# Generated deterministically by seda-macro-lef-normalizer-v1; recipe orfs-asap7-fakeram-m4-v1.
VERSION 5.8 ;
BUSBITCHARS "[]" ;
DIVIDERCHAR "/" ;

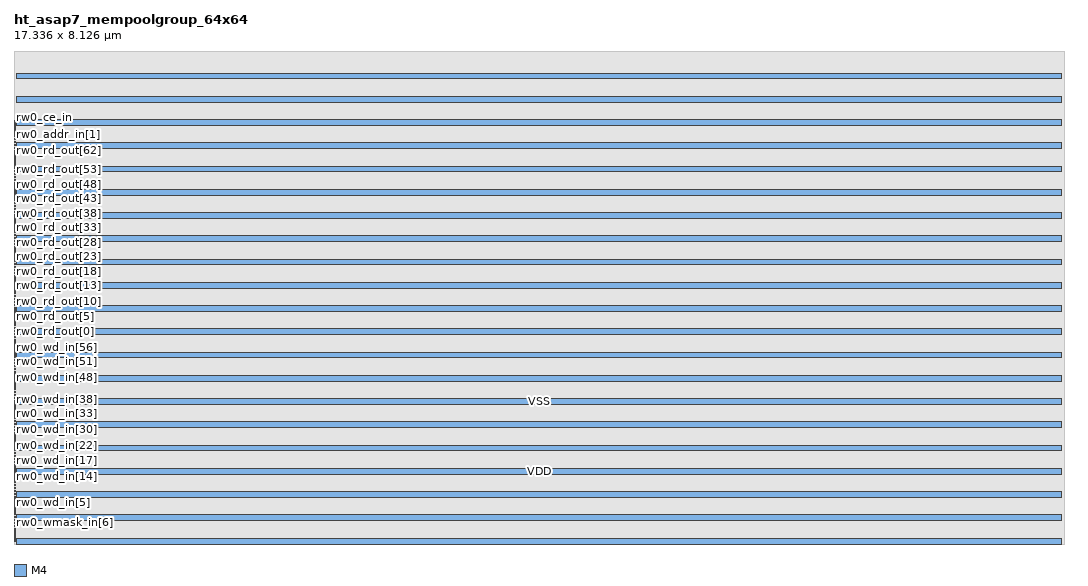
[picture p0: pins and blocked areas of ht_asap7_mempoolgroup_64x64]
MACRO ht_asap7_mempoolgroup_64x64
  FOREIGN ht_asap7_mempoolgroup_64x64 0 0 ;
  CLASS BLOCK ;
  ORIGIN 0 0 ;
  SIZE 17.336 BY 8.126 ;
  SYMMETRY X Y R90 ;
  PIN rw0_wmask_in[0]
    DIRECTION INPUT ;
    USE SIGNAL ;
    SHAPE ABUTMENT ;
    PORT
      LAYER M4 ;
      RECT 0 0.048 0.024 0.072 ;
    END
  END rw0_wmask_in[0]
  PIN rw0_wmask_in[1]
    DIRECTION INPUT ;
    USE SIGNAL ;
    SHAPE ABUTMENT ;
    PORT
      LAYER M4 ;
      RECT 0 0.096 0.024 0.12 ;
    END
  END rw0_wmask_in[1]
  PIN rw0_wmask_in[2]
    DIRECTION INPUT ;
    USE SIGNAL ;
    SHAPE ABUTMENT ;
    PORT
      LAYER M4 ;
      RECT 0 0.144 0.024 0.168 ;
    END
  END rw0_wmask_in[2]
  PIN rw0_wmask_in[3]
    DIRECTION INPUT ;
    USE SIGNAL ;
    SHAPE ABUTMENT ;
    PORT
      LAYER M4 ;
      RECT 0 0.192 0.024 0.216 ;
    END
  END rw0_wmask_in[3]
  PIN rw0_wmask_in[4]
    DIRECTION INPUT ;
    USE SIGNAL ;
    SHAPE ABUTMENT ;
    PORT
      LAYER M4 ;
      RECT 0 0.24 0.024 0.264 ;
    END
  END rw0_wmask_in[4]
  PIN rw0_wmask_in[5]
    DIRECTION INPUT ;
    USE SIGNAL ;
    SHAPE ABUTMENT ;
    PORT
      LAYER M4 ;
      RECT 0 0.288 0.024 0.312 ;
    END
  END rw0_wmask_in[5]
  PIN rw0_wmask_in[6]
    DIRECTION INPUT ;
    USE SIGNAL ;
    SHAPE ABUTMENT ;
    PORT
      LAYER M4 ;
      RECT 0 0.336 0.024 0.36 ;
    END
  END rw0_wmask_in[6]
  PIN rw0_wmask_in[7]
    DIRECTION INPUT ;
    USE SIGNAL ;
    SHAPE ABUTMENT ;
    PORT
      LAYER M4 ;
      RECT 0 0.384 0.024 0.408 ;
    END
  END rw0_wmask_in[7]
  PIN rw0_wd_in[0]
    DIRECTION INPUT ;
    USE SIGNAL ;
    SHAPE ABUTMENT ;
    PORT
      LAYER M4 ;
      RECT 0 0.432 0.024 0.456 ;
    END
  END rw0_wd_in[0]
  PIN rw0_wd_in[1]
    DIRECTION INPUT ;
    USE SIGNAL ;
    SHAPE ABUTMENT ;
    PORT
      LAYER M4 ;
      RECT 0 0.48 0.024 0.504 ;
    END
  END rw0_wd_in[1]
  PIN rw0_wd_in[2]
    DIRECTION INPUT ;
    USE SIGNAL ;
    SHAPE ABUTMENT ;
    PORT
      LAYER M4 ;
      RECT 0 0.528 0.024 0.552 ;
    END
  END rw0_wd_in[2]
  PIN rw0_wd_in[3]
    DIRECTION INPUT ;
    USE SIGNAL ;
    SHAPE ABUTMENT ;
    PORT
      LAYER M4 ;
      RECT 0 0.576 0.024 0.6 ;
    END
  END rw0_wd_in[3]
  PIN rw0_wd_in[4]
    DIRECTION INPUT ;
    USE SIGNAL ;
    SHAPE ABUTMENT ;
    PORT
      LAYER M4 ;
      RECT 0 0.624 0.024 0.648 ;
    END
  END rw0_wd_in[4]
  PIN rw0_wd_in[5]
    DIRECTION INPUT ;
    USE SIGNAL ;
    SHAPE ABUTMENT ;
    PORT
      LAYER M4 ;
      RECT 0 0.672 0.024 0.696 ;
    END
  END rw0_wd_in[5]
  PIN rw0_wd_in[6]
    DIRECTION INPUT ;
    USE SIGNAL ;
    SHAPE ABUTMENT ;
    PORT
      LAYER M4 ;
      RECT 0 0.72 0.024 0.744 ;
    END
  END rw0_wd_in[6]
  PIN rw0_wd_in[7]
    DIRECTION INPUT ;
    USE SIGNAL ;
    SHAPE ABUTMENT ;
    PORT
      LAYER M4 ;
      RECT 0 0.768 0.024 0.792 ;
    END
  END rw0_wd_in[7]
  PIN rw0_wd_in[8]
    DIRECTION INPUT ;
    USE SIGNAL ;
    SHAPE ABUTMENT ;
    PORT
      LAYER M4 ;
      RECT 0 0.816 0.024 0.84 ;
    END
  END rw0_wd_in[8]
  PIN rw0_wd_in[9]
    DIRECTION INPUT ;
    USE SIGNAL ;
    SHAPE ABUTMENT ;
    PORT
      LAYER M4 ;
      RECT 0 0.864 0.024 0.888 ;
    END
  END rw0_wd_in[9]
  PIN rw0_wd_in[10]
    DIRECTION INPUT ;
    USE SIGNAL ;
    SHAPE ABUTMENT ;
    PORT
      LAYER M4 ;
      RECT 0 0.912 0.024 0.936 ;
    END
  END rw0_wd_in[10]
  PIN rw0_wd_in[11]
    DIRECTION INPUT ;
    USE SIGNAL ;
    SHAPE ABUTMENT ;
    PORT
      LAYER M4 ;
      RECT 0 0.96 0.024 0.984 ;
    END
  END rw0_wd_in[11]
  PIN rw0_wd_in[12]
    DIRECTION INPUT ;
    USE SIGNAL ;
    SHAPE ABUTMENT ;
    PORT
      LAYER M4 ;
      RECT 0 1.008 0.024 1.032 ;
    END
  END rw0_wd_in[12]
  PIN rw0_wd_in[13]
    DIRECTION INPUT ;
    USE SIGNAL ;
    SHAPE ABUTMENT ;
    PORT
      LAYER M4 ;
      RECT 0 1.056 0.024 1.08 ;
    END
  END rw0_wd_in[13]
  PIN rw0_wd_in[14]
    DIRECTION INPUT ;
    USE SIGNAL ;
    SHAPE ABUTMENT ;
    PORT
      LAYER M4 ;
      RECT 0 1.104 0.024 1.128 ;
    END
  END rw0_wd_in[14]
  PIN rw0_wd_in[15]
    DIRECTION INPUT ;
    USE SIGNAL ;
    SHAPE ABUTMENT ;
    PORT
      LAYER M4 ;
      RECT 0 1.152 0.024 1.176 ;
    END
  END rw0_wd_in[15]
  PIN rw0_wd_in[16]
    DIRECTION INPUT ;
    USE SIGNAL ;
    SHAPE ABUTMENT ;
    PORT
      LAYER M4 ;
      RECT 0 1.2 0.024 1.224 ;
    END
  END rw0_wd_in[16]
  PIN rw0_wd_in[17]
    DIRECTION INPUT ;
    USE SIGNAL ;
    SHAPE ABUTMENT ;
    PORT
      LAYER M4 ;
      RECT 0 1.248 0.024 1.272 ;
    END
  END rw0_wd_in[17]
  PIN rw0_wd_in[18]
    DIRECTION INPUT ;
    USE SIGNAL ;
    SHAPE ABUTMENT ;
    PORT
      LAYER M4 ;
      RECT 0 1.296 0.024 1.32 ;
    END
  END rw0_wd_in[18]
  PIN rw0_wd_in[19]
    DIRECTION INPUT ;
    USE SIGNAL ;
    SHAPE ABUTMENT ;
    PORT
      LAYER M4 ;
      RECT 0 1.344 0.024 1.368 ;
    END
  END rw0_wd_in[19]
  PIN rw0_wd_in[20]
    DIRECTION INPUT ;
    USE SIGNAL ;
    SHAPE ABUTMENT ;
    PORT
      LAYER M4 ;
      RECT 0 1.392 0.024 1.416 ;
    END
  END rw0_wd_in[20]
  PIN rw0_wd_in[21]
    DIRECTION INPUT ;
    USE SIGNAL ;
    SHAPE ABUTMENT ;
    PORT
      LAYER M4 ;
      RECT 0 1.44 0.024 1.464 ;
    END
  END rw0_wd_in[21]
  PIN rw0_wd_in[22]
    DIRECTION INPUT ;
    USE SIGNAL ;
    SHAPE ABUTMENT ;
    PORT
      LAYER M4 ;
      RECT 0 1.488 0.024 1.512 ;
    END
  END rw0_wd_in[22]
  PIN rw0_wd_in[23]
    DIRECTION INPUT ;
    USE SIGNAL ;
    SHAPE ABUTMENT ;
    PORT
      LAYER M4 ;
      RECT 0 1.536 0.024 1.56 ;
    END
  END rw0_wd_in[23]
  PIN rw0_wd_in[24]
    DIRECTION INPUT ;
    USE SIGNAL ;
    SHAPE ABUTMENT ;
    PORT
      LAYER M4 ;
      RECT 0 1.584 0.024 1.608 ;
    END
  END rw0_wd_in[24]
  PIN rw0_wd_in[25]
    DIRECTION INPUT ;
    USE SIGNAL ;
    SHAPE ABUTMENT ;
    PORT
      LAYER M4 ;
      RECT 0 1.632 0.024 1.656 ;
    END
  END rw0_wd_in[25]
  PIN rw0_wd_in[26]
    DIRECTION INPUT ;
    USE SIGNAL ;
    SHAPE ABUTMENT ;
    PORT
      LAYER M4 ;
      RECT 0 1.68 0.024 1.704 ;
    END
  END rw0_wd_in[26]
  PIN rw0_wd_in[27]
    DIRECTION INPUT ;
    USE SIGNAL ;
    SHAPE ABUTMENT ;
    PORT
      LAYER M4 ;
      RECT 0 1.728 0.024 1.752 ;
    END
  END rw0_wd_in[27]
  PIN rw0_wd_in[28]
    DIRECTION INPUT ;
    USE SIGNAL ;
    SHAPE ABUTMENT ;
    PORT
      LAYER M4 ;
      RECT 0 1.776 0.024 1.8 ;
    END
  END rw0_wd_in[28]
  PIN rw0_wd_in[29]
    DIRECTION INPUT ;
    USE SIGNAL ;
    SHAPE ABUTMENT ;
    PORT
      LAYER M4 ;
      RECT 0 1.824 0.024 1.848 ;
    END
  END rw0_wd_in[29]
  PIN rw0_wd_in[30]
    DIRECTION INPUT ;
    USE SIGNAL ;
    SHAPE ABUTMENT ;
    PORT
      LAYER M4 ;
      RECT 0 1.872 0.024 1.896 ;
    END
  END rw0_wd_in[30]
  PIN rw0_wd_in[31]
    DIRECTION INPUT ;
    USE SIGNAL ;
    SHAPE ABUTMENT ;
    PORT
      LAYER M4 ;
      RECT 0 1.92 0.024 1.944 ;
    END
  END rw0_wd_in[31]
  PIN rw0_wd_in[32]
    DIRECTION INPUT ;
    USE SIGNAL ;
    SHAPE ABUTMENT ;
    PORT
      LAYER M4 ;
      RECT 0 1.968 0.024 1.992 ;
    END
  END rw0_wd_in[32]
  PIN rw0_wd_in[33]
    DIRECTION INPUT ;
    USE SIGNAL ;
    SHAPE ABUTMENT ;
    PORT
      LAYER M4 ;
      RECT 0 2.016 0.024 2.04 ;
    END
  END rw0_wd_in[33]
  PIN rw0_wd_in[34]
    DIRECTION INPUT ;
    USE SIGNAL ;
    SHAPE ABUTMENT ;
    PORT
      LAYER M4 ;
      RECT 0 2.064 0.024 2.088 ;
    END
  END rw0_wd_in[34]
  PIN rw0_wd_in[35]
    DIRECTION INPUT ;
    USE SIGNAL ;
    SHAPE ABUTMENT ;
    PORT
      LAYER M4 ;
      RECT 0 2.112 0.024 2.136 ;
    END
  END rw0_wd_in[35]
  PIN rw0_wd_in[36]
    DIRECTION INPUT ;
    USE SIGNAL ;
    SHAPE ABUTMENT ;
    PORT
      LAYER M4 ;
      RECT 0 2.16 0.024 2.184 ;
    END
  END rw0_wd_in[36]
  PIN rw0_wd_in[37]
    DIRECTION INPUT ;
    USE SIGNAL ;
    SHAPE ABUTMENT ;
    PORT
      LAYER M4 ;
      RECT 0 2.208 0.024 2.232 ;
    END
  END rw0_wd_in[37]
  PIN rw0_wd_in[38]
    DIRECTION INPUT ;
    USE SIGNAL ;
    SHAPE ABUTMENT ;
    PORT
      LAYER M4 ;
      RECT 0 2.256 0.024 2.28 ;
    END
  END rw0_wd_in[38]
  PIN rw0_wd_in[39]
    DIRECTION INPUT ;
    USE SIGNAL ;
    SHAPE ABUTMENT ;
    PORT
      LAYER M4 ;
      RECT 0 2.304 0.024 2.328 ;
    END
  END rw0_wd_in[39]
  PIN rw0_wd_in[40]
    DIRECTION INPUT ;
    USE SIGNAL ;
    SHAPE ABUTMENT ;
    PORT
      LAYER M4 ;
      RECT 0 2.352 0.024 2.376 ;
    END
  END rw0_wd_in[40]
  PIN rw0_wd_in[41]
    DIRECTION INPUT ;
    USE SIGNAL ;
    SHAPE ABUTMENT ;
    PORT
      LAYER M4 ;
      RECT 0 2.4 0.024 2.424 ;
    END
  END rw0_wd_in[41]
  PIN rw0_wd_in[42]
    DIRECTION INPUT ;
    USE SIGNAL ;
    SHAPE ABUTMENT ;
    PORT
      LAYER M4 ;
      RECT 0 2.448 0.024 2.472 ;
    END
  END rw0_wd_in[42]
  PIN rw0_wd_in[43]
    DIRECTION INPUT ;
    USE SIGNAL ;
    SHAPE ABUTMENT ;
    PORT
      LAYER M4 ;
      RECT 0 2.496 0.024 2.52 ;
    END
  END rw0_wd_in[43]
  PIN rw0_wd_in[44]
    DIRECTION INPUT ;
    USE SIGNAL ;
    SHAPE ABUTMENT ;
    PORT
      LAYER M4 ;
      RECT 0 2.544 0.024 2.568 ;
    END
  END rw0_wd_in[44]
  PIN rw0_wd_in[45]
    DIRECTION INPUT ;
    USE SIGNAL ;
    SHAPE ABUTMENT ;
    PORT
      LAYER M4 ;
      RECT 0 2.592 0.024 2.616 ;
    END
  END rw0_wd_in[45]
  PIN rw0_wd_in[46]
    DIRECTION INPUT ;
    USE SIGNAL ;
    SHAPE ABUTMENT ;
    PORT
      LAYER M4 ;
      RECT 0 2.64 0.024 2.664 ;
    END
  END rw0_wd_in[46]
  PIN rw0_wd_in[47]
    DIRECTION INPUT ;
    USE SIGNAL ;
    SHAPE ABUTMENT ;
    PORT
      LAYER M4 ;
      RECT 0 2.688 0.024 2.712 ;
    END
  END rw0_wd_in[47]
  PIN rw0_wd_in[48]
    DIRECTION INPUT ;
    USE SIGNAL ;
    SHAPE ABUTMENT ;
    PORT
      LAYER M4 ;
      RECT 0 2.736 0.024 2.76 ;
    END
  END rw0_wd_in[48]
  PIN rw0_wd_in[49]
    DIRECTION INPUT ;
    USE SIGNAL ;
    SHAPE ABUTMENT ;
    PORT
      LAYER M4 ;
      RECT 0 2.784 0.024 2.808 ;
    END
  END rw0_wd_in[49]
  PIN rw0_wd_in[50]
    DIRECTION INPUT ;
    USE SIGNAL ;
    SHAPE ABUTMENT ;
    PORT
      LAYER M4 ;
      RECT 0 2.832 0.024 2.856 ;
    END
  END rw0_wd_in[50]
  PIN rw0_wd_in[51]
    DIRECTION INPUT ;
    USE SIGNAL ;
    SHAPE ABUTMENT ;
    PORT
      LAYER M4 ;
      RECT 0 2.88 0.024 2.904 ;
    END
  END rw0_wd_in[51]
  PIN rw0_wd_in[52]
    DIRECTION INPUT ;
    USE SIGNAL ;
    SHAPE ABUTMENT ;
    PORT
      LAYER M4 ;
      RECT 0 2.928 0.024 2.952 ;
    END
  END rw0_wd_in[52]
  PIN rw0_wd_in[53]
    DIRECTION INPUT ;
    USE SIGNAL ;
    SHAPE ABUTMENT ;
    PORT
      LAYER M4 ;
      RECT 0 2.976 0.024 3 ;
    END
  END rw0_wd_in[53]
  PIN rw0_wd_in[54]
    DIRECTION INPUT ;
    USE SIGNAL ;
    SHAPE ABUTMENT ;
    PORT
      LAYER M4 ;
      RECT 0 3.024 0.024 3.048 ;
    END
  END rw0_wd_in[54]
  PIN rw0_wd_in[55]
    DIRECTION INPUT ;
    USE SIGNAL ;
    SHAPE ABUTMENT ;
    PORT
      LAYER M4 ;
      RECT 0 3.072 0.024 3.096 ;
    END
  END rw0_wd_in[55]
  PIN rw0_wd_in[56]
    DIRECTION INPUT ;
    USE SIGNAL ;
    SHAPE ABUTMENT ;
    PORT
      LAYER M4 ;
      RECT 0 3.12 0.024 3.144 ;
    END
  END rw0_wd_in[56]
  PIN rw0_wd_in[57]
    DIRECTION INPUT ;
    USE SIGNAL ;
    SHAPE ABUTMENT ;
    PORT
      LAYER M4 ;
      RECT 0 3.168 0.024 3.192 ;
    END
  END rw0_wd_in[57]
  PIN rw0_wd_in[58]
    DIRECTION INPUT ;
    USE SIGNAL ;
    SHAPE ABUTMENT ;
    PORT
      LAYER M4 ;
      RECT 0 3.216 0.024 3.24 ;
    END
  END rw0_wd_in[58]
  PIN rw0_wd_in[59]
    DIRECTION INPUT ;
    USE SIGNAL ;
    SHAPE ABUTMENT ;
    PORT
      LAYER M4 ;
      RECT 0 3.264 0.024 3.288 ;
    END
  END rw0_wd_in[59]
  PIN rw0_wd_in[60]
    DIRECTION INPUT ;
    USE SIGNAL ;
    SHAPE ABUTMENT ;
    PORT
      LAYER M4 ;
      RECT 0 3.312 0.024 3.336 ;
    END
  END rw0_wd_in[60]
  PIN rw0_wd_in[61]
    DIRECTION INPUT ;
    USE SIGNAL ;
    SHAPE ABUTMENT ;
    PORT
      LAYER M4 ;
      RECT 0 3.36 0.024 3.384 ;
    END
  END rw0_wd_in[61]
  PIN rw0_wd_in[62]
    DIRECTION INPUT ;
    USE SIGNAL ;
    SHAPE ABUTMENT ;
    PORT
      LAYER M4 ;
      RECT 0 3.408 0.024 3.432 ;
    END
  END rw0_wd_in[62]
  PIN rw0_wd_in[63]
    DIRECTION INPUT ;
    USE SIGNAL ;
    SHAPE ABUTMENT ;
    PORT
      LAYER M4 ;
      RECT 0 3.456 0.024 3.48 ;
    END
  END rw0_wd_in[63]
  PIN rw0_rd_out[0]
    DIRECTION OUTPUT ;
    USE SIGNAL ;
    SHAPE ABUTMENT ;
    PORT
      LAYER M4 ;
      RECT 0 3.504 0.024 3.528 ;
    END
  END rw0_rd_out[0]
  PIN rw0_rd_out[1]
    DIRECTION OUTPUT ;
    USE SIGNAL ;
    SHAPE ABUTMENT ;
    PORT
      LAYER M4 ;
      RECT 0 3.552 0.024 3.576 ;
    END
  END rw0_rd_out[1]
  PIN rw0_rd_out[2]
    DIRECTION OUTPUT ;
    USE SIGNAL ;
    SHAPE ABUTMENT ;
    PORT
      LAYER M4 ;
      RECT 0 3.6 0.024 3.624 ;
    END
  END rw0_rd_out[2]
  PIN rw0_rd_out[3]
    DIRECTION OUTPUT ;
    USE SIGNAL ;
    SHAPE ABUTMENT ;
    PORT
      LAYER M4 ;
      RECT 0 3.648 0.024 3.672 ;
    END
  END rw0_rd_out[3]
  PIN rw0_rd_out[4]
    DIRECTION OUTPUT ;
    USE SIGNAL ;
    SHAPE ABUTMENT ;
    PORT
      LAYER M4 ;
      RECT 0 3.696 0.024 3.72 ;
    END
  END rw0_rd_out[4]
  PIN rw0_rd_out[5]
    DIRECTION OUTPUT ;
    USE SIGNAL ;
    SHAPE ABUTMENT ;
    PORT
      LAYER M4 ;
      RECT 0 3.744 0.024 3.768 ;
    END
  END rw0_rd_out[5]
  PIN rw0_rd_out[6]
    DIRECTION OUTPUT ;
    USE SIGNAL ;
    SHAPE ABUTMENT ;
    PORT
      LAYER M4 ;
      RECT 0 3.792 0.024 3.816 ;
    END
  END rw0_rd_out[6]
  PIN rw0_rd_out[7]
    DIRECTION OUTPUT ;
    USE SIGNAL ;
    SHAPE ABUTMENT ;
    PORT
      LAYER M4 ;
      RECT 0 3.84 0.024 3.864 ;
    END
  END rw0_rd_out[7]
  PIN rw0_rd_out[8]
    DIRECTION OUTPUT ;
    USE SIGNAL ;
    SHAPE ABUTMENT ;
    PORT
      LAYER M4 ;
      RECT 0 3.888 0.024 3.912 ;
    END
  END rw0_rd_out[8]
  PIN rw0_rd_out[9]
    DIRECTION OUTPUT ;
    USE SIGNAL ;
    SHAPE ABUTMENT ;
    PORT
      LAYER M4 ;
      RECT 0 3.936 0.024 3.96 ;
    END
  END rw0_rd_out[9]
  PIN rw0_rd_out[10]
    DIRECTION OUTPUT ;
    USE SIGNAL ;
    SHAPE ABUTMENT ;
    PORT
      LAYER M4 ;
      RECT 0 3.984 0.024 4.008 ;
    END
  END rw0_rd_out[10]
  PIN rw0_rd_out[11]
    DIRECTION OUTPUT ;
    USE SIGNAL ;
    SHAPE ABUTMENT ;
    PORT
      LAYER M4 ;
      RECT 0 4.032 0.024 4.056 ;
    END
  END rw0_rd_out[11]
  PIN rw0_rd_out[12]
    DIRECTION OUTPUT ;
    USE SIGNAL ;
    SHAPE ABUTMENT ;
    PORT
      LAYER M4 ;
      RECT 0 4.08 0.024 4.104 ;
    END
  END rw0_rd_out[12]
  PIN rw0_rd_out[13]
    DIRECTION OUTPUT ;
    USE SIGNAL ;
    SHAPE ABUTMENT ;
    PORT
      LAYER M4 ;
      RECT 0 4.128 0.024 4.152 ;
    END
  END rw0_rd_out[13]
  PIN rw0_rd_out[14]
    DIRECTION OUTPUT ;
    USE SIGNAL ;
    SHAPE ABUTMENT ;
    PORT
      LAYER M4 ;
      RECT 0 4.176 0.024 4.2 ;
    END
  END rw0_rd_out[14]
  PIN rw0_rd_out[15]
    DIRECTION OUTPUT ;
    USE SIGNAL ;
    SHAPE ABUTMENT ;
    PORT
      LAYER M4 ;
      RECT 0 4.224 0.024 4.248 ;
    END
  END rw0_rd_out[15]
  PIN rw0_rd_out[16]
    DIRECTION OUTPUT ;
    USE SIGNAL ;
    SHAPE ABUTMENT ;
    PORT
      LAYER M4 ;
      RECT 0 4.272 0.024 4.296 ;
    END
  END rw0_rd_out[16]
  PIN rw0_rd_out[17]
    DIRECTION OUTPUT ;
    USE SIGNAL ;
    SHAPE ABUTMENT ;
    PORT
      LAYER M4 ;
      RECT 0 4.32 0.024 4.344 ;
    END
  END rw0_rd_out[17]
  PIN rw0_rd_out[18]
    DIRECTION OUTPUT ;
    USE SIGNAL ;
    SHAPE ABUTMENT ;
    PORT
      LAYER M4 ;
      RECT 0 4.368 0.024 4.392 ;
    END
  END rw0_rd_out[18]
  PIN rw0_rd_out[19]
    DIRECTION OUTPUT ;
    USE SIGNAL ;
    SHAPE ABUTMENT ;
    PORT
      LAYER M4 ;
      RECT 0 4.416 0.024 4.44 ;
    END
  END rw0_rd_out[19]
  PIN rw0_rd_out[20]
    DIRECTION OUTPUT ;
    USE SIGNAL ;
    SHAPE ABUTMENT ;
    PORT
      LAYER M4 ;
      RECT 0 4.464 0.024 4.488 ;
    END
  END rw0_rd_out[20]
  PIN rw0_rd_out[21]
    DIRECTION OUTPUT ;
    USE SIGNAL ;
    SHAPE ABUTMENT ;
    PORT
      LAYER M4 ;
      RECT 0 4.512 0.024 4.536 ;
    END
  END rw0_rd_out[21]
  PIN rw0_rd_out[22]
    DIRECTION OUTPUT ;
    USE SIGNAL ;
    SHAPE ABUTMENT ;
    PORT
      LAYER M4 ;
      RECT 0 4.56 0.024 4.584 ;
    END
  END rw0_rd_out[22]
  PIN rw0_rd_out[23]
    DIRECTION OUTPUT ;
    USE SIGNAL ;
    SHAPE ABUTMENT ;
    PORT
      LAYER M4 ;
      RECT 0 4.608 0.024 4.632 ;
    END
  END rw0_rd_out[23]
  PIN rw0_rd_out[24]
    DIRECTION OUTPUT ;
    USE SIGNAL ;
    SHAPE ABUTMENT ;
    PORT
      LAYER M4 ;
      RECT 0 4.656 0.024 4.68 ;
    END
  END rw0_rd_out[24]
  PIN rw0_rd_out[25]
    DIRECTION OUTPUT ;
    USE SIGNAL ;
    SHAPE ABUTMENT ;
    PORT
      LAYER M4 ;
      RECT 0 4.704 0.024 4.728 ;
    END
  END rw0_rd_out[25]
  PIN rw0_rd_out[26]
    DIRECTION OUTPUT ;
    USE SIGNAL ;
    SHAPE ABUTMENT ;
    PORT
      LAYER M4 ;
      RECT 0 4.752 0.024 4.776 ;
    END
  END rw0_rd_out[26]
  PIN rw0_rd_out[27]
    DIRECTION OUTPUT ;
    USE SIGNAL ;
    SHAPE ABUTMENT ;
    PORT
      LAYER M4 ;
      RECT 0 4.8 0.024 4.824 ;
    END
  END rw0_rd_out[27]
  PIN rw0_rd_out[28]
    DIRECTION OUTPUT ;
    USE SIGNAL ;
    SHAPE ABUTMENT ;
    PORT
      LAYER M4 ;
      RECT 0 4.848 0.024 4.872 ;
    END
  END rw0_rd_out[28]
  PIN rw0_rd_out[29]
    DIRECTION OUTPUT ;
    USE SIGNAL ;
    SHAPE ABUTMENT ;
    PORT
      LAYER M4 ;
      RECT 0 4.896 0.024 4.92 ;
    END
  END rw0_rd_out[29]
  PIN rw0_rd_out[30]
    DIRECTION OUTPUT ;
    USE SIGNAL ;
    SHAPE ABUTMENT ;
    PORT
      LAYER M4 ;
      RECT 0 4.944 0.024 4.968 ;
    END
  END rw0_rd_out[30]
  PIN rw0_rd_out[31]
    DIRECTION OUTPUT ;
    USE SIGNAL ;
    SHAPE ABUTMENT ;
    PORT
      LAYER M4 ;
      RECT 0 4.992 0.024 5.016 ;
    END
  END rw0_rd_out[31]
  PIN rw0_rd_out[32]
    DIRECTION OUTPUT ;
    USE SIGNAL ;
    SHAPE ABUTMENT ;
    PORT
      LAYER M4 ;
      RECT 0 5.04 0.024 5.064 ;
    END
  END rw0_rd_out[32]
  PIN rw0_rd_out[33]
    DIRECTION OUTPUT ;
    USE SIGNAL ;
    SHAPE ABUTMENT ;
    PORT
      LAYER M4 ;
      RECT 0 5.088 0.024 5.112 ;
    END
  END rw0_rd_out[33]
  PIN rw0_rd_out[34]
    DIRECTION OUTPUT ;
    USE SIGNAL ;
    SHAPE ABUTMENT ;
    PORT
      LAYER M4 ;
      RECT 0 5.136 0.024 5.16 ;
    END
  END rw0_rd_out[34]
  PIN rw0_rd_out[35]
    DIRECTION OUTPUT ;
    USE SIGNAL ;
    SHAPE ABUTMENT ;
    PORT
      LAYER M4 ;
      RECT 0 5.184 0.024 5.208 ;
    END
  END rw0_rd_out[35]
  PIN rw0_rd_out[36]
    DIRECTION OUTPUT ;
    USE SIGNAL ;
    SHAPE ABUTMENT ;
    PORT
      LAYER M4 ;
      RECT 0 5.232 0.024 5.256 ;
    END
  END rw0_rd_out[36]
  PIN rw0_rd_out[37]
    DIRECTION OUTPUT ;
    USE SIGNAL ;
    SHAPE ABUTMENT ;
    PORT
      LAYER M4 ;
      RECT 0 5.28 0.024 5.304 ;
    END
  END rw0_rd_out[37]
  PIN rw0_rd_out[38]
    DIRECTION OUTPUT ;
    USE SIGNAL ;
    SHAPE ABUTMENT ;
    PORT
      LAYER M4 ;
      RECT 0 5.328 0.024 5.352 ;
    END
  END rw0_rd_out[38]
  PIN rw0_rd_out[39]
    DIRECTION OUTPUT ;
    USE SIGNAL ;
    SHAPE ABUTMENT ;
    PORT
      LAYER M4 ;
      RECT 0 5.376 0.024 5.4 ;
    END
  END rw0_rd_out[39]
  PIN rw0_rd_out[40]
    DIRECTION OUTPUT ;
    USE SIGNAL ;
    SHAPE ABUTMENT ;
    PORT
      LAYER M4 ;
      RECT 0 5.424 0.024 5.448 ;
    END
  END rw0_rd_out[40]
  PIN rw0_rd_out[41]
    DIRECTION OUTPUT ;
    USE SIGNAL ;
    SHAPE ABUTMENT ;
    PORT
      LAYER M4 ;
      RECT 0 5.472 0.024 5.496 ;
    END
  END rw0_rd_out[41]
  PIN rw0_rd_out[42]
    DIRECTION OUTPUT ;
    USE SIGNAL ;
    SHAPE ABUTMENT ;
    PORT
      LAYER M4 ;
      RECT 0 5.52 0.024 5.544 ;
    END
  END rw0_rd_out[42]
  PIN rw0_rd_out[43]
    DIRECTION OUTPUT ;
    USE SIGNAL ;
    SHAPE ABUTMENT ;
    PORT
      LAYER M4 ;
      RECT 0 5.568 0.024 5.592 ;
    END
  END rw0_rd_out[43]
  PIN rw0_rd_out[44]
    DIRECTION OUTPUT ;
    USE SIGNAL ;
    SHAPE ABUTMENT ;
    PORT
      LAYER M4 ;
      RECT 0 5.616 0.024 5.64 ;
    END
  END rw0_rd_out[44]
  PIN rw0_rd_out[45]
    DIRECTION OUTPUT ;
    USE SIGNAL ;
    SHAPE ABUTMENT ;
    PORT
      LAYER M4 ;
      RECT 0 5.664 0.024 5.688 ;
    END
  END rw0_rd_out[45]
  PIN rw0_rd_out[46]
    DIRECTION OUTPUT ;
    USE SIGNAL ;
    SHAPE ABUTMENT ;
    PORT
      LAYER M4 ;
      RECT 0 5.712 0.024 5.736 ;
    END
  END rw0_rd_out[46]
  PIN rw0_rd_out[47]
    DIRECTION OUTPUT ;
    USE SIGNAL ;
    SHAPE ABUTMENT ;
    PORT
      LAYER M4 ;
      RECT 0 5.76 0.024 5.784 ;
    END
  END rw0_rd_out[47]
  PIN rw0_rd_out[48]
    DIRECTION OUTPUT ;
    USE SIGNAL ;
    SHAPE ABUTMENT ;
    PORT
      LAYER M4 ;
      RECT 0 5.808 0.024 5.832 ;
    END
  END rw0_rd_out[48]
  PIN rw0_rd_out[49]
    DIRECTION OUTPUT ;
    USE SIGNAL ;
    SHAPE ABUTMENT ;
    PORT
      LAYER M4 ;
      RECT 0 5.856 0.024 5.88 ;
    END
  END rw0_rd_out[49]
  PIN rw0_rd_out[50]
    DIRECTION OUTPUT ;
    USE SIGNAL ;
    SHAPE ABUTMENT ;
    PORT
      LAYER M4 ;
      RECT 0 5.904 0.024 5.928 ;
    END
  END rw0_rd_out[50]
  PIN rw0_rd_out[51]
    DIRECTION OUTPUT ;
    USE SIGNAL ;
    SHAPE ABUTMENT ;
    PORT
      LAYER M4 ;
      RECT 0 5.952 0.024 5.976 ;
    END
  END rw0_rd_out[51]
  PIN rw0_rd_out[52]
    DIRECTION OUTPUT ;
    USE SIGNAL ;
    SHAPE ABUTMENT ;
    PORT
      LAYER M4 ;
      RECT 0 6 0.024 6.024 ;
    END
  END rw0_rd_out[52]
  PIN rw0_rd_out[53]
    DIRECTION OUTPUT ;
    USE SIGNAL ;
    SHAPE ABUTMENT ;
    PORT
      LAYER M4 ;
      RECT 0 6.048 0.024 6.072 ;
    END
  END rw0_rd_out[53]
  PIN rw0_rd_out[54]
    DIRECTION OUTPUT ;
    USE SIGNAL ;
    SHAPE ABUTMENT ;
    PORT
      LAYER M4 ;
      RECT 0 6.096 0.024 6.12 ;
    END
  END rw0_rd_out[54]
  PIN rw0_rd_out[55]
    DIRECTION OUTPUT ;
    USE SIGNAL ;
    SHAPE ABUTMENT ;
    PORT
      LAYER M4 ;
      RECT 0 6.144 0.024 6.168 ;
    END
  END rw0_rd_out[55]
  PIN rw0_rd_out[56]
    DIRECTION OUTPUT ;
    USE SIGNAL ;
    SHAPE ABUTMENT ;
    PORT
      LAYER M4 ;
      RECT 0 6.192 0.024 6.216 ;
    END
  END rw0_rd_out[56]
  PIN rw0_rd_out[57]
    DIRECTION OUTPUT ;
    USE SIGNAL ;
    SHAPE ABUTMENT ;
    PORT
      LAYER M4 ;
      RECT 0 6.24 0.024 6.264 ;
    END
  END rw0_rd_out[57]
  PIN rw0_rd_out[58]
    DIRECTION OUTPUT ;
    USE SIGNAL ;
    SHAPE ABUTMENT ;
    PORT
      LAYER M4 ;
      RECT 0 6.288 0.024 6.312 ;
    END
  END rw0_rd_out[58]
  PIN rw0_rd_out[59]
    DIRECTION OUTPUT ;
    USE SIGNAL ;
    SHAPE ABUTMENT ;
    PORT
      LAYER M4 ;
      RECT 0 6.336 0.024 6.36 ;
    END
  END rw0_rd_out[59]
  PIN rw0_rd_out[60]
    DIRECTION OUTPUT ;
    USE SIGNAL ;
    SHAPE ABUTMENT ;
    PORT
      LAYER M4 ;
      RECT 0 6.384 0.024 6.408 ;
    END
  END rw0_rd_out[60]
  PIN rw0_rd_out[61]
    DIRECTION OUTPUT ;
    USE SIGNAL ;
    SHAPE ABUTMENT ;
    PORT
      LAYER M4 ;
      RECT 0 6.432 0.024 6.456 ;
    END
  END rw0_rd_out[61]
  PIN rw0_rd_out[62]
    DIRECTION OUTPUT ;
    USE SIGNAL ;
    SHAPE ABUTMENT ;
    PORT
      LAYER M4 ;
      RECT 0 6.48 0.024 6.504 ;
    END
  END rw0_rd_out[62]
  PIN rw0_rd_out[63]
    DIRECTION OUTPUT ;
    USE SIGNAL ;
    SHAPE ABUTMENT ;
    PORT
      LAYER M4 ;
      RECT 0 6.528 0.024 6.552 ;
    END
  END rw0_rd_out[63]
  PIN rw0_addr_in[0]
    DIRECTION INPUT ;
    USE SIGNAL ;
    SHAPE ABUTMENT ;
    PORT
      LAYER M4 ;
      RECT 0 6.576 0.024 6.6 ;
    END
  END rw0_addr_in[0]
  PIN rw0_addr_in[1]
    DIRECTION INPUT ;
    USE SIGNAL ;
    SHAPE ABUTMENT ;
    PORT
      LAYER M4 ;
      RECT 0 6.624 0.024 6.648 ;
    END
  END rw0_addr_in[1]
  PIN rw0_addr_in[2]
    DIRECTION INPUT ;
    USE SIGNAL ;
    SHAPE ABUTMENT ;
    PORT
      LAYER M4 ;
      RECT 0 6.672 0.024 6.696 ;
    END
  END rw0_addr_in[2]
  PIN rw0_addr_in[3]
    DIRECTION INPUT ;
    USE SIGNAL ;
    SHAPE ABUTMENT ;
    PORT
      LAYER M4 ;
      RECT 0 6.72 0.024 6.744 ;
    END
  END rw0_addr_in[3]
  PIN rw0_addr_in[4]
    DIRECTION INPUT ;
    USE SIGNAL ;
    SHAPE ABUTMENT ;
    PORT
      LAYER M4 ;
      RECT 0 6.768 0.024 6.792 ;
    END
  END rw0_addr_in[4]
  PIN rw0_addr_in[5]
    DIRECTION INPUT ;
    USE SIGNAL ;
    SHAPE ABUTMENT ;
    PORT
      LAYER M4 ;
      RECT 0 6.816 0.024 6.84 ;
    END
  END rw0_addr_in[5]
  PIN rw0_we_in
    DIRECTION INPUT ;
    USE SIGNAL ;
    SHAPE ABUTMENT ;
    PORT
      LAYER M4 ;
      RECT 0 6.864 0.024 6.888 ;
    END
  END rw0_we_in
  PIN rw0_ce_in
    DIRECTION INPUT ;
    USE SIGNAL ;
    SHAPE ABUTMENT ;
    PORT
      LAYER M4 ;
      RECT 0 6.912 0.024 6.936 ;
    END
  END rw0_ce_in
  PIN rw0_clk
    DIRECTION INPUT ;
    USE SIGNAL ;
    SHAPE ABUTMENT ;
    PORT
      LAYER M4 ;
      RECT 0 6.96 0.024 6.984 ;
    END
  END rw0_clk
  PIN VSS
    DIRECTION INOUT ;
    USE GROUND ;
    PORT
      LAYER M4 ;
      RECT 0.048 0 17.288 0.096 ;
      RECT 0.048 0.768 17.288 0.864 ;
      RECT 0.048 1.536 17.288 1.632 ;
      RECT 0.048 2.304 17.288 2.4 ;
      RECT 0.048 3.072 17.288 3.168 ;
      RECT 0.048 3.84 17.288 3.936 ;
      RECT 0.048 4.608 17.288 4.704 ;
      RECT 0.048 5.376 17.288 5.472 ;
      RECT 0.048 6.144 17.288 6.24 ;
      RECT 0.048 6.912 17.288 7.008 ;
      RECT 0.048 7.68 17.288 7.776 ;
    END
  END VSS
  PIN VDD
    DIRECTION INOUT ;
    USE POWER ;
    PORT
      LAYER M4 ;
      RECT 0.048 0.384 17.288 0.48 ;
      RECT 0.048 1.152 17.288 1.248 ;
      RECT 0.048 1.92 17.288 2.016 ;
      RECT 0.048 2.688 17.288 2.784 ;
      RECT 0.048 3.456 17.288 3.552 ;
      RECT 0.048 4.224 17.288 4.32 ;
      RECT 0.048 4.992 17.288 5.088 ;
      RECT 0.048 5.76 17.288 5.856 ;
      RECT 0.048 6.528 17.288 6.624 ;
      RECT 0.048 7.296 17.288 7.392 ;
    END
  END VDD
  OBS
    LAYER M1 ;
    RECT 0 0 17.336 8.126 ;
    LAYER M2 ;
    RECT 0 0 17.336 8.126 ;
    LAYER M3 ;
    RECT 0 0 17.336 8.126 ;
  END
END ht_asap7_mempoolgroup_64x64

END LIBRARY
